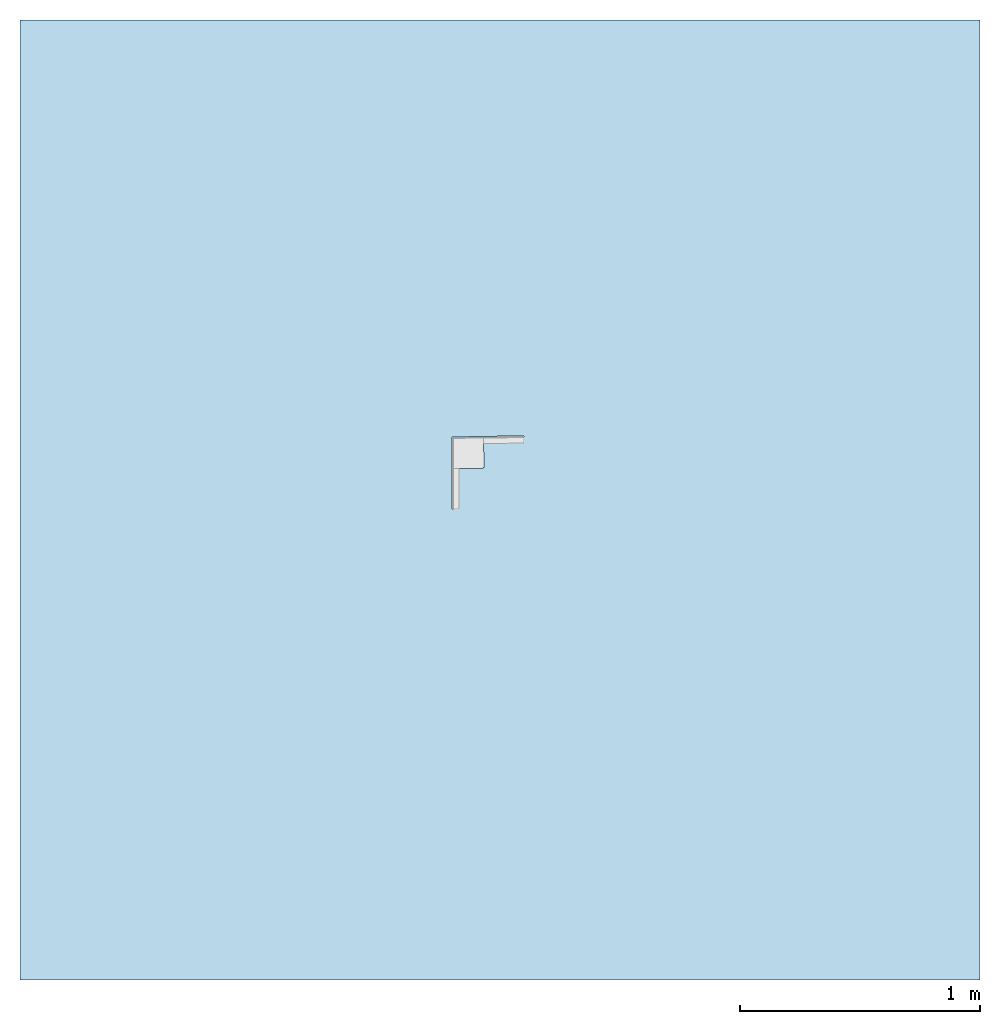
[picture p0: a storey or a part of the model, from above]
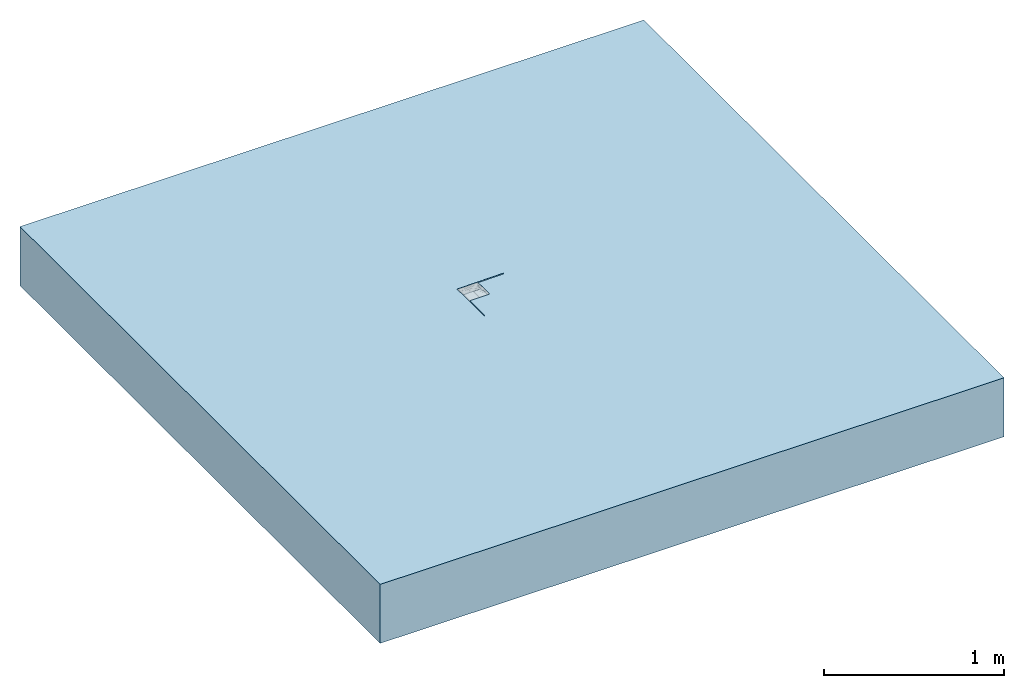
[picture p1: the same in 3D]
Properties of the parts of a building model (IFC2X3)

# File
Description: ViewDefinition [CoordinationView]
File name: Project Number
Time: 2014-06-06T11:23:38
Written by: The EXPRESS Data Manager Version 5.01.0100.02.64mod : 6 Jun 2012
Made in: 20130308_1515(x64) - Exporter 2014.0.2013.0308 - Default UI
Comment: STEP Physical File produced by: The EXPRESS Data Manager Version 5.01.0100.02.64mod : 6 Jun 2012 * Module: EDMstepFileFactory/EDMstandAlone * Creation date: Fri Jun 06 11:23:38 2014 * Host: IN-BLR-PC-0010 * Database: C:\Users\palleri\AppData\Local\Temp\{6ED7EBD7-7C56-4424-90EC-685606667773}\ifc * Database version: 5507 * Database creation date: Fri Jun 06 11:23:38 2014 * Schema: IFC2X3 * Model: DataRepository.ifc * Model creation date: Fri Jun 06 11:23:38 2014 * Header model: DataRepository.ifc_HeaderModel * Header model creation date: Fri Jun 06 11:23:38 2014 * EDMuser: sdai-user * EDMgroup: sdai-group * License ID and type: 5605 : Permanent license. Expiry date: * EDMstepFileFactory options: 020000

# IfcProject, Project Number
LongName: Project Name; Phase: Project Status

# IfcSite, Default
RefLatitude: 42, 21, 30, 344238; RefLongitude: -71, -3, -35, -194702; RefElevation: 0 mm

# IfcBuilding
Pset_BuildingCommon - NumberOfStoreys: 1
Other - Project Status: Project Status; Client Name: Owner; Project Issue Date: Issue Date; Project Name: Project Name; Project Number: Project Number; Project Address: ## Street City, State Zip

# IfcBuildingStorey, Level 1
LongName: Level 1; Elevation: 0 mm
Constraints - Elevation Base: Project Base Point; Elevation: 0 mm
Graphics - Symbol at End 1 Default: no; Symbol at End 2 Default: yes; Color: 0; Symbol: M_Level Head - Circle: M_Level Head - Circle; Line Weight: 1; Line Pattern: Center
Identity Data - Building Story: yes; Structural: no; Name: Level 1
Dimensions - Computation Height: 0 mm

# IfcFlowTerminal: 38643 - Adjustable Corner - Adjustable Height Channel, ACO Freedeck Adjustable Length (Accessories part 2) V1.12 - Stainless Steel:38643 - Adjustable Corner - Adjustable Height Channel:280767
In: Level 1
Material: Stainless Steel Grade 304
Dimensions - Corner Angle Void Position: 0 mm; Height @ Invert 1: 165 mm; Adjustable Corner Angle: 91 deg; Corner Angle Gravel Guard: 73 mm; Channel End Length: -600 mm; Channel Length: 600 mm; Grating End Length: 600 mm; Height @ Invert 2: 165 mm
Other - Top Piece Void Height @ Invert 1: 31 mm; Height @ Invert 2 Min & Max: 5000 mm; Nos: 20; Corner Angle Value: 91 deg; Height @ Invert 1 Min & Max: 5000 mm; Corner Angle Invert Height Min & Max: 75 mm; Top Piece Void Height @ Invert 2: 31 mm; Adjustable Length Deep Section: no; Corner Angle Fixed Height: yes; Corner Angle Adjustable Height: no; Top Void Position: 5000 mm; Top Height: 50 mm; Adjustable Length Shallow Section: no; Base Height: 46 mm; Adjustable Length Channel: no; Adjustable Length Intermediate Section: no
Identity Data - Mark: 16; Telephone: +44 (0)1462 816666; E-mail Technical: abdtechnical@aco.co.uk; Watermarked With: BIM Manager Premium Suite; Website: www.acobd.com; Fax: +44 (0)1462 851490; E-mail Sales: abdcommercial@aco.co.uk; Watermarked By: www.acobd.com; Watermark1: This file is the property of ACO Technologies PLC; Address: ACO Business Centre, Caxton Road, Bedford, MK41 0LF; Manufacturer: ACO Building Drainage; Watermark2: This file is water marked and users are prohibited to reproduce, adapt, distribute this information
Phasing - Phase Created: New Construction
Constraints - Level: Level: Level 1; Moves With Nearby Elements: no
Construction - Corner Angle Shallow Section: no; 36954 - Grating - Plain Mesh - Stainless Steel 304 - 500mm long: yes; Corner Angle Intermediate Section: no; 00273 - Grating - Slotted Grating - Stainless Steel 304 - 500mm long: no
Pset_ManufacturerTypeInformation - Manufacturer: ACO Building Drainage
General - Product Type: Linear Deck Drainage System; Channel Recycled Material Content: 60 - 70 %; Load Class: A15; Maintenance Guidelines: X:\Electronic Literature\ABD Electronic Literature\Roof and Balcony Drainage\ACO Freedeck Brochure.pdf; Product Code: 38643; Price: POA - contact ACO; Dimensions (LxWxH): 300 x 300; Product Standard: BS EN 1433:2002, CE marked; Product Description: ACO Freedeck Adjustable Corner - Adjustable channel section only; Channel Recyclable: Fully recyclable; Channel Colour: Mid Grey; Channel Material: Stainless Steel Grade 304; NBS Specification: NBS Section R10 Gravity Rainwater Drainage Systems, Subsection 365; Installation Guidelines: X:\Electronic Literature\ABD Electronic Literature\Roof and Balcony Drainage\ACO Freedeck Brochure.pdf; Weight (Kg): 1.5kg; Product Range: ACO Freedeck
Materials and Finishes - Material: Stainless Steel Grade 304
Model Properties - Grating Product Code 00273: N/A; Grating Product Code 36954: N/A

# IfcOpeningElement: Recess (2)
In: Level 1
Structural - Enable Analytical Model: no; Structural: no
Constraints - Height Offset From Level: 0 mm; Related to Mass: no; Level: Level: Level 1; Room Bounding: yes
Phasing - Phase Created: New Construction
Dimensions - Volume: 6.39762 m3; Area: 16 m2; Thickness: 400 mm; Perimeter: 16000 mm
Materials and Finishes - Structural Material: Concrete, Broom Finish
Analytical Properties - Absorptance: 0.1; Thermal mass: 604440; Heat Transfer Coefficient (U): 2.615; Thermal Resistance (R): 0.382409; Roughness: 1
Graphics - Coarse Scale Fill Color: 0
Construction - Function: Interior; Default Thickness: 400 mm

# IfcSlab: Floor:Generic Floor - 400mm, Floor:Generic Floor - 400mm:193825
In: Level 1
PredefinedType: FLOOR; Material: Concrete, Broom Finish 400 mm
Structural - Enable Analytical Model: no; Structural: no
Constraints - Height Offset From Level: 0 mm; Related to Mass: no; Level: Level: Level 1; Room Bounding: yes
Phasing - Phase Created: New Construction
Dimensions - Volume: 6.39762 m3; Area: 16 m2; Thickness: 400 mm; Perimeter: 16000 mm
Pset_SlabCommon - Reference: Generic Floor - 400mm; IsExternal: no; LoadBearing: yes; ThermalTransmittance: 2.615 kg/K/s3
Materials and Finishes - Structural Material: Concrete, Broom Finish
Analytical Properties - Absorptance: 0.1; Thermal mass: 604440; Heat Transfer Coefficient (U): 2.615; Thermal Resistance (R): 0.382409; Roughness: 1
Graphics - Coarse Scale Fill Color: 0
Construction - Function: Interior; Default Thickness: 400 mm
